# Handwritten synthetic technology for H3D development; not a fabrication PDK.
VERSION 5.8 ;
BUSBITCHARS "[]" ;
DIVIDERCHAR "/" ;

UNITS
  DATABASE MICRONS 2000 ;
END UNITS
MANUFACTURINGGRID 0.001 ;

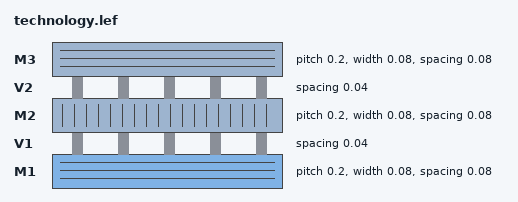
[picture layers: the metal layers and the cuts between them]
LAYER M1
  TYPE ROUTING ;
  DIRECTION HORIZONTAL ;
  PITCH 0.2 ;
  WIDTH 0.08 ;
  MINWIDTH 0.08 ;
  AREA 0.016 ;
  SPACING 0.08 ;
  SPACINGTABLE
    PARALLELRUNLENGTH 0.0
    WIDTH 0.0 0.08 ;
END M1

LAYER V1
  TYPE CUT ;
  SPACING 0.04 ;
END V1

LAYER M2
  TYPE ROUTING ;
  DIRECTION VERTICAL ;
  PITCH 0.2 ;
  WIDTH 0.08 ;
  MINWIDTH 0.08 ;
  AREA 0.016 ;
  SPACING 0.08 ;
  SPACINGTABLE
    PARALLELRUNLENGTH 0.0
    WIDTH 0.0 0.08 ;
END M2

LAYER V2
  TYPE CUT ;
  SPACING 0.04 ;
END V2

LAYER M3
  TYPE ROUTING ;
  DIRECTION HORIZONTAL ;
  PITCH 0.2 ;
  WIDTH 0.08 ;
  MINWIDTH 0.08 ;
  AREA 0.016 ;
  SPACING 0.08 ;
  SPACINGTABLE
    PARALLELRUNLENGTH 0.0
    WIDTH 0.0 0.08 ;
END M3

VIA VIA12 DEFAULT
  LAYER M1 ;
    RECT -0.04 -0.04 0.04 0.04 ;
  LAYER V1 ;
    RECT -0.02 -0.02 0.02 0.02 ;
  LAYER M2 ;
    RECT -0.04 -0.04 0.04 0.04 ;
END VIA12

VIA VIA23 DEFAULT
  LAYER M2 ;
    RECT -0.04 -0.04 0.04 0.04 ;
  LAYER V2 ;
    RECT -0.02 -0.02 0.02 0.02 ;
  LAYER M3 ;
    RECT -0.04 -0.04 0.04 0.04 ;
END VIA23

SITE unitSite
  CLASS CORE ;
  SYMMETRY X Y ;
  SIZE 1.0 BY 1.0 ;
END unitSite

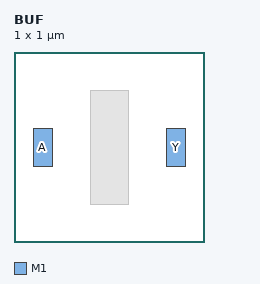
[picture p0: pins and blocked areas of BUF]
MACRO BUF
  CLASS CORE ;
  ORIGIN 0.0 0.0 ;
  SIZE 1.0 BY 1.0 ;
  SYMMETRY X Y ;
  SITE unitSite ;
  PIN A
    DIRECTION INPUT ;
    USE SIGNAL ;
    PORT
      LAYER M1 ;
        RECT 0.10 0.40 0.20 0.60 ;
    END
  END A
  PIN Y
    DIRECTION OUTPUT ;
    USE SIGNAL ;
    PORT
      LAYER M1 ;
        RECT 0.80 0.40 0.90 0.60 ;
    END
  END Y
  OBS
    LAYER M2 ;
      RECT 0.40 0.20 0.60 0.80 ;
  END
END BUF

END LIBRARY
